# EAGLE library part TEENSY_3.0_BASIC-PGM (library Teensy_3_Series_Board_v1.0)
Teensy 3.0 Board outline identical to other 'basic' version except that 'PGM' pin has been omitted. See '+4', 'AllAnalogPins", and 'AllPins' packages for additional pin holes, as needed.

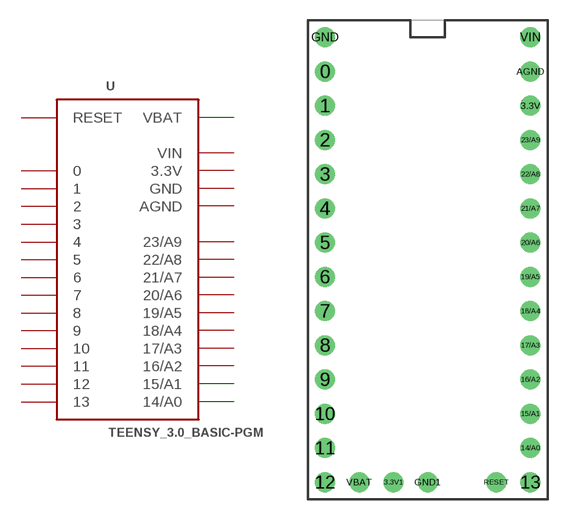
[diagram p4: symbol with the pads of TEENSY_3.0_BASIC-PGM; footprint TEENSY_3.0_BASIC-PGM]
Designator prefix -

## TEENSY_3.0_BASIC-PGM  [TEENSY_3.0_BASIC-PGM]
0  0
1  1
2  2
3  3
3.3V  3.3V  pwr
3.3V1  3.3V  pwr
4  4
5  5
6  6
7  7
8  8
9  9
10  10
11  11
12  12
13  13
14/A0  14/A0
15/A1  15/A1
16/A2  16/A2
17/A3  17/A3
18/A4  18/A4
19/A5  19/A5
20/A6  20/A6
21/A7  21/A7
22/A8  22/A8
23/A9  23/A9
AGND  AGND  pwr
GND  GND  pwr
GND1  GND  pwr
RESET  RESET
VBAT  VBAT  pwr
VIN  VIN  pwr

## Footprint TEENSY_3.0_BASIC-PGM (pad centres in mm)
drill 0.965: 0 -7.62,13.97; 1 -7.62,11.43; 2 -7.62,8.89; 3 -7.62,6.35; 3.3V 7.62,11.43; 3.3V1 -2.54,-16.51; 4 -7.62,3.81; 5 -7.62,1.27; 6 -7.62,-1.27; 7 -7.62,-3.81; 8 -7.62,-6.35; 9 -7.62,-8.89; 10 -7.62,-11.43; 11 -7.62,-13.97; 12 -7.62,-16.51; 13 7.62,-16.51; 14/A0 7.62,-13.97; 15/A1 7.62,-11.43; 16/A2 7.62,-8.89; 17/A3 7.62,-6.35; 18/A4 7.62,-3.81; 19/A5 7.62,-1.27; 20/A6 7.62,1.27; 21/A7 7.62,3.81; 22/A8 7.62,6.35; 23/A9 7.62,8.89; AGND 7.62,13.97; GND -7.62,16.51; GND1 0,-16.51; RESET 5.08,-16.51; VBAT -5.08,-16.51; VIN 7.62,16.51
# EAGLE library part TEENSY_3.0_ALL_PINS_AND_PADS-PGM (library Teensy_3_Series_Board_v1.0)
Teensy 3.0 board outline with all pins and pads enabled except 'PGM' pin. For more basic versions, see 'Basic', '+4', and 'AllAnalogPins'. Requires the installation of a un-shrouded SMD header on the underside of the Teensy 3.0

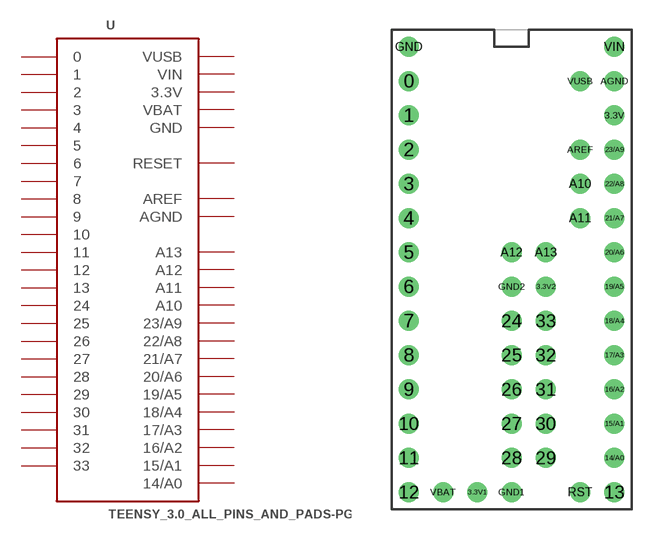
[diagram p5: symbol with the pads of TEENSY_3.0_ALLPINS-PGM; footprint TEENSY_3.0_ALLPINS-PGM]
Designator prefix -

## TEENSY_3.0_ALL_PINS_AND_PADS-PGM  [TEENSY_3.0_ALLPINS-PGM]
0  0
1  1
2  2
3  3
3.3V  3.3V  pwr
3.3V1  3.3V  pwr
3.3V2  3.3V  pwr
4  4
5  5
6  6
7  7
8  8
9  9
10  10
11  11
12  12
13  13
14/A0  14/A0
15/A1  15/A1
16/A2  16/A2
17/A3  17/A3
18/A4  18/A4
19/A5  19/A5
20/A6  20/A6
21/A7  21/A7
22/A8  22/A8
23/A9  23/A9
24  24
25  25
26  26
27  27
28  28
29  29
30  30
31  31
32  32
33  33
A10  A10
A11  A11
A12  A12
A13  A13
AGND  AGND  pwr
AREF  AREF  pwr
GND  GND  pwr
GND1  GND  pwr
GND2  GND  pwr
RST  RESET
VBAT  VBAT  pwr
VIN  VIN  pwr
VUSB  VUSB  pwr

## Footprint TEENSY_3.0_ALLPINS-PGM (pad centres in mm)
drill 0.965: 0 -6.35,16.51; 1 -6.35,13.97; 2 -6.35,11.43; 3 -6.35,8.89; 3.3V 8.89,13.97; 3.3V1 -1.27,-13.97; 3.3V2 3.81,1.27; 4 -6.35,6.35; 5 -6.35,3.81; 6 -6.35,1.27; 7 -6.35,-1.27; 8 -6.35,-3.81; 9 -6.35,-6.35; 10 -6.35,-8.89; 11 -6.35,-11.43; 12 -6.35,-13.97; 13 8.89,-13.97; 14/A0 8.89,-11.43; 15/A1 8.89,-8.89; 16/A2 8.89,-6.35; 17/A3 8.89,-3.81; 18/A4 8.89,-1.27; 19/A5 8.89,1.27; 20/A6 8.89,3.81; 21/A7 8.89,6.35; 22/A8 8.89,8.89; 23/A9 8.89,11.43; 24 1.27,-1.27; 25 1.27,-3.81; 26 1.27,-6.35; 27 1.27,-8.89; 28 1.27,-11.43; 29 3.81,-11.43; 30 3.81,-8.89; 31 3.81,-6.35; 32 3.81,-3.81; 33 3.81,-1.27; A10 6.35,8.89; A11 6.35,6.35; A12 1.27,3.81; A13 3.81,3.81; AGND 8.89,16.51; AREF 6.35,11.43; GND -6.35,19.05; GND1 1.27,-13.97; GND2 1.27,1.27; RST 6.35,-13.97; VBAT -3.81,-13.97; VIN 8.89,19.05; VUSB 6.35,16.51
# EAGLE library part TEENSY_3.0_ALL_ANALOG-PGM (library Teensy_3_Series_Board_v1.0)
Teensy 3.0 outline with all Analog Input Pins and Pads enabled, PGM Pin is disabled. For more basic versions, see 'Basic' and '+4' while more pins are accessible in the 'AllPins' package. Requires the installation of a un-shrouded SMD header on the underside of the Teensy 3.0

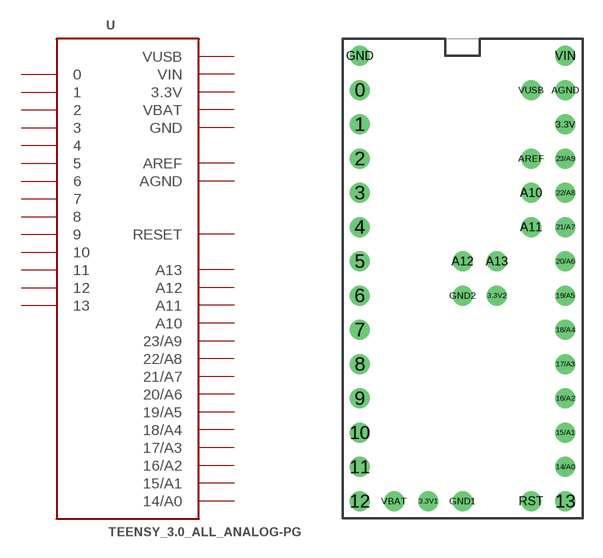
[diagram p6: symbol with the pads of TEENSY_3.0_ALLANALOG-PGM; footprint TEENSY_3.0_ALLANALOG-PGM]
Designator prefix -

## TEENSY_3.0_ALL_ANALOG-PGM  [TEENSY_3.0_ALLANALOG-PGM]
0  0
1  1
2  2
3  3
3.3V  3.3V  pwr
3.3V1  3.3V  pwr
3.3V2  3.3V  pwr
4  4
5  5
6  6
7  7
8  8
9  9
10  10
11  11
12  12
13  13
14/A0  14/A0
15/A1  15/A1
16/A2  16/A2
17/A3  17/A3
18/A4  18/A4
19/A5  19/A5
20/A6  20/A6
21/A7  21/A7
22/A8  22/A8
23/A9  23/A9
A10  A10
A11  A11
A12  A12
A13  A13
AGND  AGND  pwr
AREF  AREF  pwr
GND  GND  pwr
GND1  GND  pwr
GND2  GND  pwr
RST  RESET  pwr
VBAT  VBAT  pwr
VIN  VIN  pwr
VUSB  VUSB  pwr

## Footprint TEENSY_3.0_ALLANALOG-PGM (pad centres in mm)
drill 0.965: 0 -7.62,13.97; 1 -7.62,11.43; 2 -7.62,8.89; 3 -7.62,6.35; 3.3V 7.62,11.43; 3.3V1 -2.54,-16.51; 3.3V2 2.54,-1.27; 4 -7.62,3.81; 5 -7.62,1.27; 6 -7.62,-1.27; 7 -7.62,-3.81; 8 -7.62,-6.35; 9 -7.62,-8.89; 10 -7.62,-11.43; 11 -7.62,-13.97; 12 -7.62,-16.51; 13 7.62,-16.51; 14/A0 7.62,-13.97; 15/A1 7.62,-11.43; 16/A2 7.62,-8.89; 17/A3 7.62,-6.35; 18/A4 7.62,-3.81; 19/A5 7.62,-1.27; 20/A6 7.62,1.27; 21/A7 7.62,3.81; 22/A8 7.62,6.35; 23/A9 7.62,8.89; A10 5.08,6.35; A11 5.08,3.81; A12 0,1.27; A13 2.54,1.27; AGND 7.62,13.97; AREF 5.08,8.89; GND -7.62,16.51; GND1 0,-16.51; GND2 0,-1.27; RST 5.08,-16.51; VBAT -5.08,-16.51; VIN 7.62,16.51; VUSB 5.08,13.97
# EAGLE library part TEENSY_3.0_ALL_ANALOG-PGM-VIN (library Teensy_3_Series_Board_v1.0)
Teensy 3.0 outline with all Analog Input Pins and Pads enabled, PGM and VIN Pins are disabled. For more basic versions, see 'Basic' and '+4' while more pins are accessible in the 'AllPins' package. Requires the installation of a un-shrouded SMD header on the underside of the Teensy 3.0

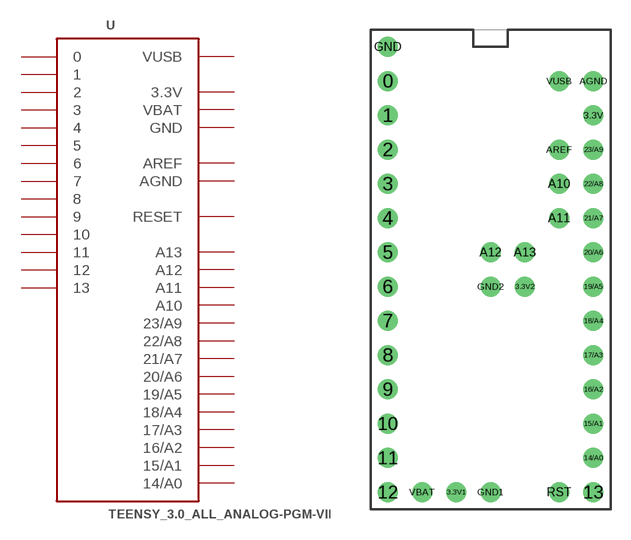
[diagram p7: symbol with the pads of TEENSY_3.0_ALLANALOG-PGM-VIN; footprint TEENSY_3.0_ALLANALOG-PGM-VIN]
Designator prefix -

## TEENSY_3.0_ALL_ANALOG-PGM-VIN  [TEENSY_3.0_ALLANALOG-PGM-VIN]
0  0
1  1
2  2
3  3
3.3V  3.3V  pwr
3.3V1  3.3V  pwr
3.3V2  3.3V  pwr
4  4
5  5
6  6
7  7
8  8
9  9
10  10
11  11
12  12
13  13
14/A0  14/A0
15/A1  15/A1
16/A2  16/A2
17/A3  17/A3
18/A4  18/A4
19/A5  19/A5
20/A6  20/A6
21/A7  21/A7
22/A8  22/A8
23/A9  23/A9
A10  A10
A11  A11
A12  A12
A13  A13
AGND  AGND  pwr
AREF  AREF  pwr
GND  GND  pwr
GND1  GND  pwr
GND2  GND  pwr
RST  RESET  pwr
VBAT  VBAT  pwr
VUSB  VUSB  pwr

## Footprint TEENSY_3.0_ALLANALOG-PGM-VIN (pad centres in mm)
drill 0.965: 0 -7.62,15.24; 1 -7.62,12.7; 2 -7.62,10.16; 3 -7.62,7.62; 3.3V 7.62,12.7; 3.3V1 -2.54,-15.24; 3.3V2 2.54,0; 4 -7.62,5.08; 5 -7.62,2.54; 6 -7.62,0; 7 -7.62,-2.54; 8 -7.62,-5.08; 9 -7.62,-7.62; 10 -7.62,-10.16; 11 -7.62,-12.7; 12 -7.62,-15.24; 13 7.62,-15.24; 14/A0 7.62,-12.7; 15/A1 7.62,-10.16; 16/A2 7.62,-7.62; 17/A3 7.62,-5.08; 18/A4 7.62,-2.54; 19/A5 7.62,0; 20/A6 7.62,2.54; 21/A7 7.62,5.08; 22/A8 7.62,7.62; 23/A9 7.62,10.16; A10 5.08,7.62; A11 5.08,5.08; A12 0,2.54; A13 2.54,2.54; AGND 7.62,15.24; AREF 5.08,10.16; GND -7.62,17.78; GND1 0,-15.24; GND2 0,0; RST 5.08,-15.24; VBAT -5.08,-15.24; VUSB 5.08,15.24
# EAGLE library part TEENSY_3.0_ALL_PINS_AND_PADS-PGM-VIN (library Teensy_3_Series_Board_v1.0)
Teensy 3.0 board outline with all pins and pads enabled except 'PGM' and 'VIN' pins. For more basic versions, see 'Basic', '+4', and 'AllAnalogPins'. Requires the installation of a un-shrouded SMD header on the underside of the Teensy 3.0

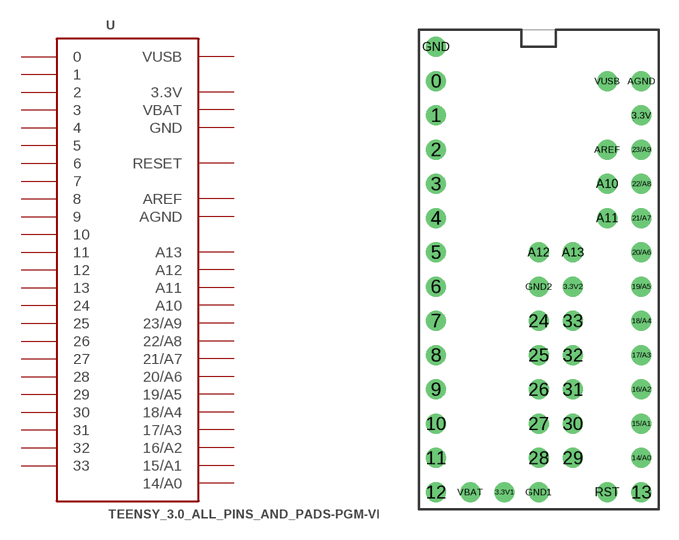
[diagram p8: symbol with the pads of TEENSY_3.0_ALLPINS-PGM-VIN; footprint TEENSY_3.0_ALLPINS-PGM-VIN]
Designator prefix -

## TEENSY_3.0_ALL_PINS_AND_PADS-PGM-VIN  [TEENSY_3.0_ALLPINS-PGM-VIN]
0  0
1  1
2  2
3  3
3.3V  3.3V  pwr
3.3V1  3.3V  pwr
3.3V2  3.3V  pwr
4  4
5  5
6  6
7  7
8  8
9  9
10  10
11  11
12  12
13  13
14/A0  14/A0
15/A1  15/A1
16/A2  16/A2
17/A3  17/A3
18/A4  18/A4
19/A5  19/A5
20/A6  20/A6
21/A7  21/A7
22/A8  22/A8
23/A9  23/A9
24  24
25  25
26  26
27  27
28  28
29  29
30  30
31  31
32  32
33  33
A10  A10
A11  A11
A12  A12
A13  A13
AGND  AGND  pwr
AREF  AREF  pwr
GND  GND  pwr
GND1  GND  pwr
GND2  GND  pwr
RST  RESET
VBAT  VBAT  pwr
VUSB  VUSB  pwr

## Footprint TEENSY_3.0_ALLPINS-PGM-VIN (pad centres in mm)
drill 0.965: 0 -7.62,16.51; 1 -7.62,13.97; 2 -7.62,11.43; 3 -7.62,8.89; 3.3V 7.62,13.97; 3.3V1 -2.54,-13.97; 3.3V2 2.54,1.27; 4 -7.62,6.35; 5 -7.62,3.81; 6 -7.62,1.27; 7 -7.62,-1.27; 8 -7.62,-3.81; 9 -7.62,-6.35; 10 -7.62,-8.89; 11 -7.62,-11.43; 12 -7.62,-13.97; 13 7.62,-13.97; 14/A0 7.62,-11.43; 15/A1 7.62,-8.89; 16/A2 7.62,-6.35; 17/A3 7.62,-3.81; 18/A4 7.62,-1.27; 19/A5 7.62,1.27; 20/A6 7.62,3.81; 21/A7 7.62,6.35; 22/A8 7.62,8.89; 23/A9 7.62,11.43; 24 0,-1.27; 25 0,-3.81; 26 0,-6.35; 27 0,-8.89; 28 0,-11.43; 29 2.54,-11.43; 30 2.54,-8.89; 31 2.54,-6.35; 32 2.54,-3.81; 33 2.54,-1.27; A10 5.08,8.89; A11 5.08,6.35; A12 0,3.81; A13 2.54,3.81; AGND 7.62,16.51; AREF 5.08,11.43; GND -7.62,19.05; GND1 0,-13.97; GND2 0,1.27; RST 5.08,-13.97; VBAT -5.08,-13.97; VUSB 5.08,16.51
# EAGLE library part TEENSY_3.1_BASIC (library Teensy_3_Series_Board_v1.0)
Footprint for Teensy 3.1 board using all pin connections on the outer perimeter

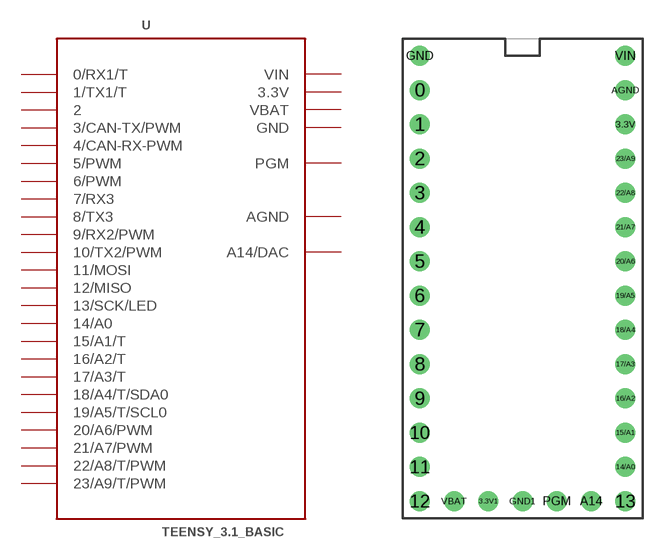
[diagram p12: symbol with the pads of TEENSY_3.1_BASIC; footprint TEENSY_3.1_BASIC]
Designator prefix -

## TEENSY_3.1_BASIC  [TEENSY_3.1_BASIC]
0  0/RX1/T
1  1/TX1/T
2  2
3  3/CAN-TX/PWM
3.3V  3.3V  pwr
3.3V1  3.3V  pwr
4  4/CAN-RX-PWM
5  5/PWM
6  6/PWM
7  7/RX3
8  8/TX3
9  9/RX2/PWM
10  10/TX2/PWM
11  11/MOSI
12  12/MISO
13  13/SCK/LED
14/A0  14/A0
15/A1  15/A1/T
16/A2  16/A2/T
17/A3  17/A3/T
18/A4  18/A4/T/SDA0
19/A5  19/A5/T/SCL0
20/A6  20/A6/PWM
21/A7  21/A7/PWM
22/A8  22/A8/T/PWM
23/A9  23/A9/T/PWM
A14  A14/DAC
AGND  AGND  pwr
GND  GND  pwr
GND1  GND  pwr
PGM  PGM
VBAT  VBAT  pwr
VIN  VIN  pwr

## Footprint TEENSY_3.1_BASIC (pad centres in mm)
drill 0.965: 0 -7.62,13.97; 1 -7.62,11.43; 2 -7.62,8.89; 3 -7.62,6.35; 3.3V 7.62,11.43; 3.3V1 -2.54,-16.51; 4 -7.62,3.81; 5 -7.62,1.27; 6 -7.62,-1.27; 7 -7.62,-3.81; 8 -7.62,-6.35; 9 -7.62,-8.89; 10 -7.62,-11.43; 11 -7.62,-13.97; 12 -7.62,-16.51; 13 7.62,-16.51; 14/A0 7.62,-13.97; 15/A1 7.62,-11.43; 16/A2 7.62,-8.89; 17/A3 7.62,-6.35; 18/A4 7.62,-3.81; 19/A5 7.62,-1.27; 20/A6 7.62,1.27; 21/A7 7.62,3.81; 22/A8 7.62,6.35; 23/A9 7.62,8.89; A14 5.08,-16.51; AGND 7.62,13.97; GND -7.62,16.51; GND1 0,-16.51; PGM 2.54,-16.51; VBAT -5.08,-16.51; VIN 7.62,16.51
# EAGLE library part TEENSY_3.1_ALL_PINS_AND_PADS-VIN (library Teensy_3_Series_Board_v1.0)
Footprint for Teensy 3.1 board using all pads and all through-holes, with the exception of the VIN pin. Use this option if you want to use an external voltage regulator for the Teensy. Pads need a 2x7 0.1" SMD header.

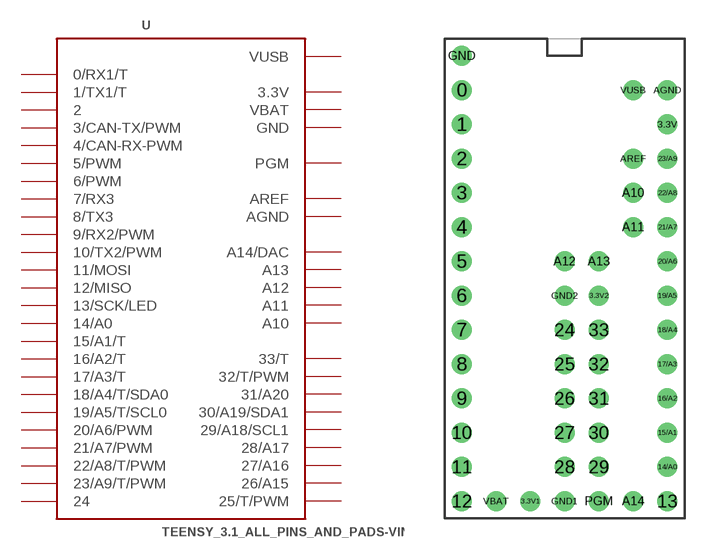
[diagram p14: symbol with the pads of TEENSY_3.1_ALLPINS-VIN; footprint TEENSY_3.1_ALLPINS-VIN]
Designator prefix -

## TEENSY_3.1_ALL_PINS_AND_PADS-VIN  [TEENSY_3.1_ALLPINS-VIN]
0  0/RX1/T
1  1/TX1/T
2  2
3  3/CAN-TX/PWM
3.3V  3.3V  pwr
3.3V1  3.3V  pwr
3.3V2  3.3V  pwr
4  4/CAN-RX-PWM
5  5/PWM
6  6/PWM
7  7/RX3
8  8/TX3
9  9/RX2/PWM
10  10/TX2/PWM
11  11/MOSI
12  12/MISO
13  13/SCK/LED
14/A0  14/A0
15/A1  15/A1/T
16/A2  16/A2/T
17/A3  17/A3/T
18/A4  18/A4/T/SDA0
19/A5  19/A5/T/SCL0
20/A6  20/A6/PWM
21/A7  21/A7/PWM
22/A8  22/A8/T/PWM
23/A9  23/A9/T/PWM
24  24
25  25/T/PWM
26  26/A15
27  27/A16
28  28/A17
29  29/A18/SCL1
30  30/A19/SDA1
31  31/A20
32  32/T/PWM
33  33/T
A10  A10
A11  A11
A12  A12
A13  A13
A14  A14/DAC
AGND  AGND  pwr
AREF  AREF  pwr
GND  GND  pwr
GND1  GND  pwr
GND2  GND  pwr
PGM  PGM
VBAT  VBAT  pwr
VUSB  VUSB  pwr

## Footprint TEENSY_3.1_ALLPINS-VIN (pad centres in mm)
drill 0.965: 0 -7.62,15.24; 1 -7.62,12.7; 2 -7.62,10.16; 3 -7.62,7.62; 3.3V 7.62,12.7; 3.3V1 -2.54,-15.24; 3.3V2 2.54,0; 4 -7.62,5.08; 5 -7.62,2.54; 6 -7.62,0; 7 -7.62,-2.54; 8 -7.62,-5.08; 9 -7.62,-7.62; 10 -7.62,-10.16; 11 -7.62,-12.7; 12 -7.62,-15.24; 13 7.62,-15.24; 14/A0 7.62,-12.7; 15/A1 7.62,-10.16; 16/A2 7.62,-7.62; 17/A3 7.62,-5.08; 18/A4 7.62,-2.54; 19/A5 7.62,0; 20/A6 7.62,2.54; 21/A7 7.62,5.08; 22/A8 7.62,7.62; 23/A9 7.62,10.16; 24 0,-2.54; 25 0,-5.08; 26 0,-7.62; 27 0,-10.16; 28 0,-12.7; 29 2.54,-12.7; 30 2.54,-10.16; 31 2.54,-7.62; 32 2.54,-5.08; 33 2.54,-2.54; A10 5.08,7.62; A11 5.08,5.08; A12 0,2.54; A13 2.54,2.54; A14 5.08,-15.24; AGND 7.62,15.24; AREF 5.08,10.16; GND -7.62,17.78; GND1 0,-15.24; GND2 0,0; PGM 2.54,-15.24; VBAT -5.08,-15.24; VUSB 5.08,15.24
